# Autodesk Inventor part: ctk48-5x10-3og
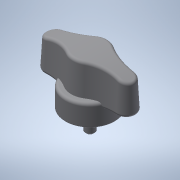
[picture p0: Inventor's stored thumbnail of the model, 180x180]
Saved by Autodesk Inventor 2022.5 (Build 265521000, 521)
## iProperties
Created: 2016-12
Part Number: ctk48-5x10-3og
Material: 一般
Document SubType Name: Modeling
Designer: imaocorp
Density: 1 g/cm^3
Appearance: 既定
Author: imaocorp
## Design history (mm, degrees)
node "ctk48-5x10-3og.x_t1"
node "ctk48-5x10-3og"
node "Base1"
